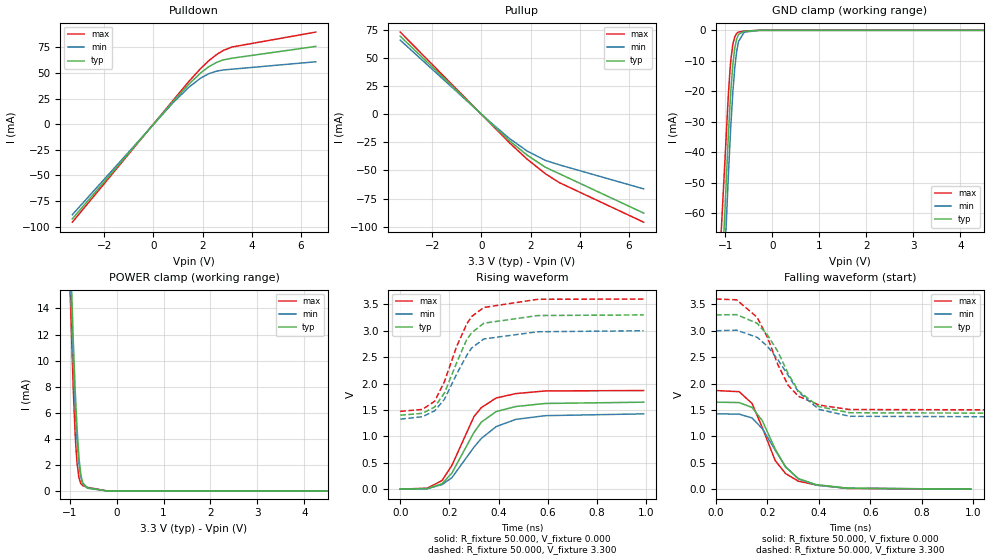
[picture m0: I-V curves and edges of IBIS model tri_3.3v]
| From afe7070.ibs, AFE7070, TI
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[Model]   tri_3.3v
Model_type 3-state
Vref=0.000E+00
Rref=1.000E+06
Cref=0.000E+00
Vmeas=1.650E+00
C_comp   4.8400E-13   4.7500E-13   4.9300E-13
[Voltage Range]   3.300E+00   3.000E+00   3.600E+00
[POWER Clamp Reference]   3.300E+00   3.000E+00   3.600E+00
[GND Clamp Reference]   0.000E+00   0.000E+00   0.000E+00
[Pullup Reference]   3.300E+00   3.000E+00   3.600E+00
[Pulldown Reference]   0.000E+00   0.000E+00   0.000E+00
[Temperature Range]   25   85  -40
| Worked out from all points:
|   slope of the pulldown table from 0 to 0.495 V, typ, clamps not added: 35.8 ohm
|   slope of the pullup table from 0 to 0.495 V, typ, clamps not added: 48.5 ohm
|   GND clamp passes 1 mA (typ) near -0.70 V on its own axis
|   POWER clamp passes 1 mA (typ) near -0.75 V on its own axis
|   rising waveform, R_fixture 50.000, V_fixture 0.000: 20-80 % time 128ps typ, 149ps min, 118ps max; typ from 0 V to 1.65 V
|   falling waveform, R_fixture 50.000, V_fixture 0.000: 20-80 % time 108ps typ, 115ps min, 101ps max; typ from 1.65 V to 0 V
|   rising waveform, R_fixture 50.000, V_fixture 3.300: 20-80 % time 109ps typ, 118ps min, 108ps max; typ from 1.4 V to 3.3 V
|   falling waveform, R_fixture 50.000, V_fixture 3.300: 20-80 % time 137ps typ, 148ps min, 125ps max; typ from 3.3 V to 1.4 V
[GND Clamp]
-3.3V     -826mA     -879.8mA   -717.6mA
-1.02V    -62.59mA   -77.21mA   -45.89mA
-940mV    -35.58mA   -48.9mA    -22.01mA
-900mV    -23.92mA   -36.01mA   -12.69mA
-880mV    -18.95mA   -30.21mA   -9.211mA
-840mV    -11.03mA   -20.14mA   -4.496mA
-800mV    -5.818mA   -12.33mA   -2.102mA
-760mV    -2.856mA   -6.926mA   -1.035mA
-720mV    -1.36mA    -3.656mA   -563.4uA
-600mV    -310.4uA   -607.3uA   -241.4uA
-280mV    0A         0A         0A
6.6V      0A         0A         0A
[Power Clamp]
-3.3V     283.4mA    254.2mA    276.7mA
-1.02V    22.77mA    20.23mA    18.9mA
-920mV    11.43mA    10.06mA    7.72mA
-880mV    7.747mA    6.684mA    4.33mA
-860mV    6.2mA      5.228mA    3.077mA
-840mV    4.811mA    3.97mA     2.132mA
-800mV    2.561mA    2.114mA    1.016mA
-760mV    1.243mA    1.064mA    563.3uA
-720mV    622.7uA    586.8uA    407.3uA
-620mV    235.1uA    206.4uA    278uA
-200mV    0A         0A         0A
6.6V      0A         0A         0A
[Pullup]
-3.3V     69.46mA    65.96mA    73.14mA
340mV     -7.096mA   -6.576mA   -7.499mA
1.14V     -23.57mA   -21.53mA   -25.34mA
1.86V     -36.36mA   -32.74mA   -39.95mA
2.6V      -47.13mA   -41.02mA   -52.88mA
3.16V     -52.82mA   -44.96mA   -60.74mA
6.6V      -87.95mA   -66.43mA   -96.07mA
[Pulldown]
-3.3V     -92.37mA   -88.32mA   -95.62mA
800mV     22.26mA    21mA       23.29mA
1.44V     38.99mA    36.1mA     41.68mA
1.92V     50.01mA    44.98mA    54.35mA
2.24V     55.92mA    49.15mA    61.74mA
2.56V     60.25mA    51.72mA    67.83mA
2.84V     62.75mA    52.91mA    71.98mA
3.2V      64.39mA    53.67mA    75.33mA
6.6V      75.88mA    60.91mA    89.86mA
[Rising Waveform]
R_fixture = 50.000
V_fixture = 0.000
V_fixture_min = 0.000
V_fixture_max = 0.000
|  time   V(typ)   V(min)   V(max)
0s        0V         0V         0V
110ps     9.795mV    8.721mV    19.16mV
170ps     103.4mV    86.18mV    163.6mV
210ps     303.9mV    216.9mV    449.4mV
300ps     1.076V     796.1mV    1.376V
330ps     1.27V      961.5mV    1.545V
390ps     1.469V     1.184V     1.726V
470ps     1.565V     1.322V     1.81V
590ps     1.623V     1.392V     1.86V
990ps     1.647V     1.426V     1.868V
[Falling Waveform]
R_fixture = 50.000
V_fixture = 0.000
V_fixture_min = 0.000
V_fixture_max = 0.000
|  time   V(typ)   V(min)   V(max)
0s        1.647V     1.426V     1.868V
90ps      1.64V      1.421V     1.846V
140ps     1.548V     1.348V     1.623V
180ps     1.296V     1.146V     1.164V
230ps     758.7mV    737.7mV    541.9mV
270ps     418.1mV    427.8mV    296.5mV
320ps     200mV      192.5mV    150.7mV
390ps     85.95mV    73.79mV    79.93mV
510ps     19.51mV    17mV       14.52mV
990ps     0V         0V         0V
[Rising Waveform]
R_fixture = 50.000
V_fixture = 3.300
V_fixture_min = 3.000
V_fixture_max = 3.600
|  time   V(typ)   V(min)   V(max)
0s        1.401V     1.325V     1.473V
90ps      1.436V     1.372V     1.51V
140ps     1.556V     1.483V     1.665V
180ps     1.824V     1.704V     2.039V
230ps     2.4V       2.185V     2.709V
270ps     2.83V      2.53V      3.124V
290ps     2.959V     2.671V     3.268V
340ps     3.143V     2.845V     3.441V
560ps     3.288V     2.981V     3.596V
990ps     3.3V       3V         3.6V
[Falling Waveform]
R_fixture = 50.000
V_fixture = 3.300
V_fixture_min = 3.000
V_fixture_max = 3.600
|  time   V(typ)   V(min)   V(max)
0s        3.3V       3V         3.6V
80ps      3.305V     3.01V      3.586V
160ps     3.141V     2.876V     3.254V
200ps     2.919V     2.705V     2.872V
240ps     2.609V     2.456V     2.362V
280ps     2.191V     2.157V     1.968V
320ps     1.86V      1.841V     1.76V
400ps     1.562V     1.51V      1.593V
520ps     1.447V     1.38V      1.508V
3.96ns    1.401V     1.325V     1.473V
[Ramp]
dV/dt_r   9.6100E-01/1.2760E-10  8.5600E-01/1.4940E-10  1.1039E+00/1.2271E-10
dV/dt_f   1.1400E+00/1.3350E-10  1.0050E+00/1.4660E-10  1.2769E+00/1.2553E-10
R_load = 50
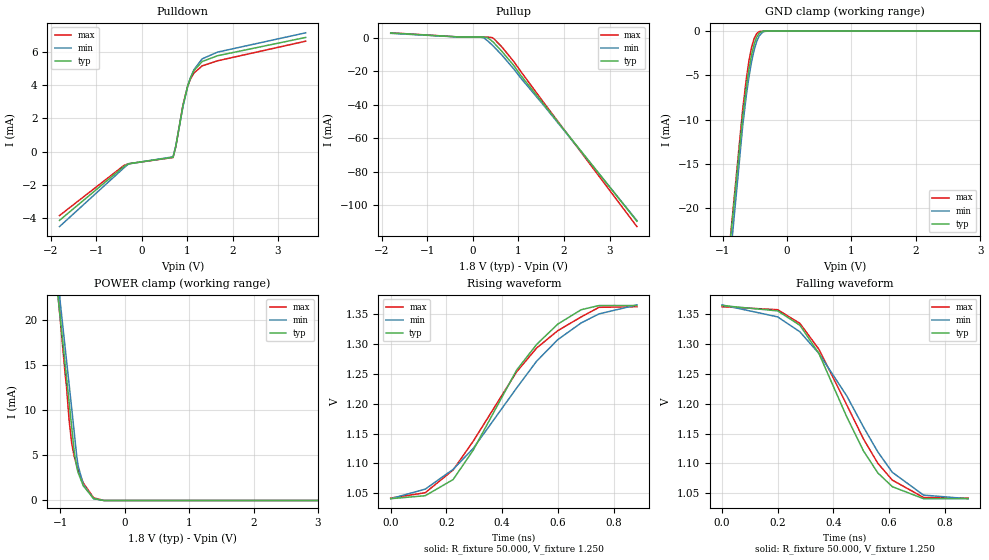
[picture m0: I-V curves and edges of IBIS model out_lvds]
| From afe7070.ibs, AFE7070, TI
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[Model]   out_lvds
Model_type 3-state
Vref=1.200E+00
Rref=5.000E+01
Cref=5.000E-12
Vmeas=1.1800E+00
C_comp   2.000E-12   2.000E-12   2.000E-12
[Voltage Range]   1.800E+00   1.710E+00   1.890E+00
[POWER Clamp Reference]   1.800E+00   1.710E+00   1.890E+00
[GND Clamp Reference]   0.000E+00   0.000E+00   0.000E+00
[Pullup Reference]   1.800E+00   1.710E+00   1.890E+00
[Pulldown Reference]   0.000E+00   0.000E+00   0.000E+00
[Temperature Range]   25   85   -40
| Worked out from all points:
|   slope of the pulldown table from 0 to 0.27 V, typ, clamps not added: 3.07 kohm
|   slope of the pullup table from 0 to 0.27 V, typ, clamps not added: 2.84 kohm
|   GND clamp passes 1 mA (typ) near -0.49 V on its own axis
|   POWER clamp passes 1 mA (typ) near -0.59 V on its own axis
|   rising waveform, R_fixture 50.000, V_fixture 1.250: 20-80 % time 250ps typ, 322ps min, 283ps max; typ from 1.04 V to 1.36 V
|   falling waveform, R_fixture 50.000, V_fixture 1.250: 20-80 % time 198ps typ, 258ps min, 213ps max; typ from 1.36 V to 1.04 V
[GND Clamp]
-1.81V    -91.27mA   -97.56mA   -93.54mA
-770mV    -15.72mA   -17.15mA   -15.12mA
-690mV    -9.84mA    -10.89mA   -9.02mA
-630mV    -6.288mA   -7.202mA   -5.343mA
-590mV    -4.304mA   -5.159mA   -3.358mA
-550mV    -2.694mA   -3.471mA   -1.851mA
-510mV    -1.491mA   -2.146mA   -848.1uA
-470mV    -687.4uA   -1.172mA   -289.3uA
-430mV    -233.2uA   -528.8uA   -53.24uA
-370mV    -6.521uA   -74.99uA   -11.55uA
-290mV    0A         0A         0A
3.6V      0A         0A         0A
[Power Clamp]
-1.8V     74.7mA     75.08mA    83.43mA
-920mV    14.99mA    16.84mA    13.92mA
-900mV    13.63mA    15.52mA    12.6mA
-860mV    10.92mA    12.87mA    8.891mA
-820mV    8.136mA    10.23mA    6.329mA
-780mV    5.342mA    7.514mA    4.853mA
-740mV    3.657mA    4.786mA    3.822mA
-720mV    3.093mA    3.851mA    3.385mA
-640mV    1.623mA    1.765mA    1.944mA
-480mV    207.7uA    195.1uA    297.6uA
-320mV    0A         0A         0A
3.6V      0A         0A         0A
[Pullup]
-1.8V     2.883mA    2.641mA    2.972mA
-340mV    544.5uA    506uA      563.7uA
160mV     459uA      407.7uA    490uA
240mV     435.4uA    -68.21uA   479.8uA
320mV     130.3uA    -1.686mA   462uA
420mV     -1.882mA   -4.169mA   130.5uA
460mV     -2.91mA    -5.249mA   -524.6uA
640mV     -8.166mA   -10.38mA   -5.526mA
900mV     -16.6mA    -18.68mA   -14.25mA
1.06V     -22.76mA   -24.31mA   -20.38mA
1.56V     -39.85mA   -40.5mA    -38.89mA
3.6V      -109.7mA   -109.3mA   -112.9mA
[Pulldown]
-1.81V    -4.125mA   -4.497mA   -3.835mA
-390mV    -888.8uA   -969uA     -826.2uA
-290mV    -723.6uA   -738.6uA   -727.6uA
690mV     -337.5uA   -311.3uA   -351.8uA
750mV     304uA      332.2uA    296.1uA
910mV     2.779mA    2.726mA    2.83mA
1.01V     3.914mA    3.883mA    3.91mA
1.07V     4.404mA    4.405mA    4.34mA
1.15V     4.858mA    4.916mA    4.714mA
1.33V     5.403mA    5.564mA    5.142mA
1.67V     5.753mA    5.97mA     5.449mA
3.61V     6.849mA    7.127mA    6.625mA
[Rising Waveform]
R_fixture = 50.000
V_fixture = 1.250
V_fixture_min = 1.250
V_fixture_max = 1.250
|  time   V(typ)   V(min)   V(max)
0s        1.041V     1.041V     1.042V
124ps     1.046V     1.057V     1.051V
224ps     1.073V     1.09V      1.089V
296ps     1.122V     1.125V     1.137V
452ps     1.256V     1.226V     1.253V
524ps     1.299V     1.271V     1.293V
600ps     1.333V     1.307V     1.322V
684ps     1.357V     1.335V     1.345V
748ps     1.364V     1.35V      1.361V
884ps     1.364V     1.365V     1.362V
[Falling Waveform]
R_fixture = 50.000
V_fixture = 1.250
V_fixture_min = 1.250
V_fixture_max = 1.250
|  time   V(typ)   V(min)   V(max)
0s        1.364V     1.365V     1.362V
200ps     1.355V     1.345V     1.357V
280ps     1.331V     1.32V      1.334V
348ps     1.284V     1.284V     1.291V
448ps     1.178V     1.213V     1.198V
508ps     1.121V     1.161V     1.141V
560ps     1.084V     1.119V     1.1V
612ps     1.061V     1.085V     1.072V
724ps     1.041V     1.047V     1.043V
884ps     1.041V     1.041V     1.042V
[Ramp]
dV/dt_r   1.9398E-01/3.0234E-10   1.9386E-01/3.7639E-10   1.9182E-01/3.4299E-10
dV/dt_f   1.9398E-01/2.0723E-10   1.9386E-01/2.6057E-10   1.9182E-01/2.0662E-10
R_load = 50
